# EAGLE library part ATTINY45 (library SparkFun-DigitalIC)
Atmel 8-pin 2/4/8kB flash uC

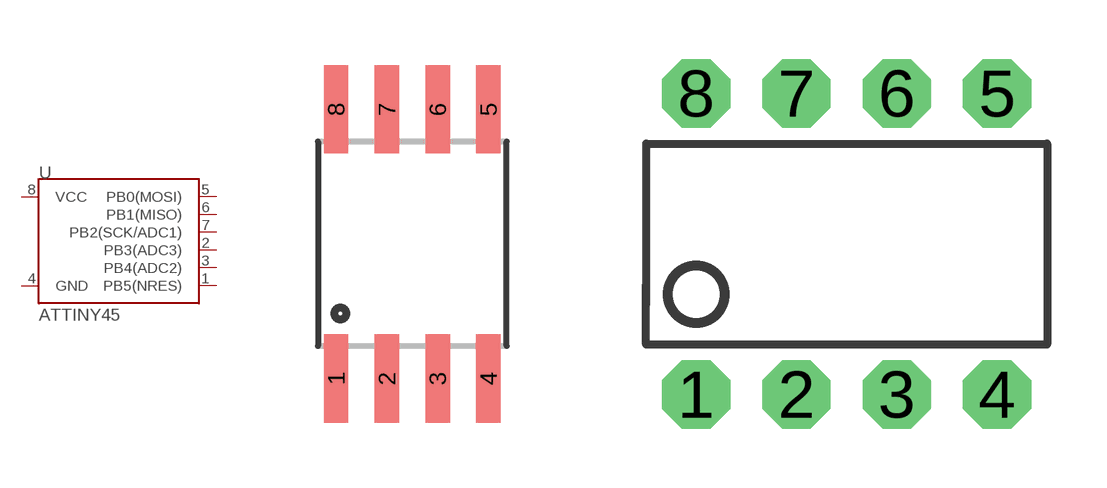
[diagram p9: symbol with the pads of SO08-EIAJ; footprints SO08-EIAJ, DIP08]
Designator prefix U

## ATTINY45TINY45-20-SMT (PROD_ID: IC-08922; VALUE: Tiny45-20-SMT)  [SO08-EIAJ]
1  PB5(NRES)
2  PB3(ADC3)
3  PB4(ADC2)
4  GND
5  PB0(MOSI)
6  PB1(MISO)
7  PB2(SCK/ADC1)
8  VCC

## ATTINY45TINY45-20-DIP (PROD_ID: IC-09439; VALUE: TINY45-20-DIP)  [DIP08]
Pads as for SO08-EIAJ

## ATTINY45TINY85-20-DIP (PROD_ID: IC-09445; VALUE: TINY85-20-DIP)  [DIP08]
Pads as for SO08-EIAJ

## ATTINY45TINY85-20-SMT (PROD_ID: IC-09092; VALUE: Tiny85-20-SMT)  [SO08-EIAJ]
Pads as for SO08-EIAJ

## Footprint SO08-EIAJ (pad centres in mm)
Fits EIAJ packages (wide version of the SOIC-8).
smd 0.61 x 2.21: 1 -1.905,-3.378; 2 -0.635,-3.378; 3 0.635,-3.378; 4 1.905,-3.378; 5 1.905,3.353; 6 0.635,3.353; 7 -0.635,3.353; 8 -1.905,3.353

## Footprint DIP08 (pad centres in mm)
Dual In Line
drill 0.813 pad 1.727 octagon: 1 -3.81,-3.81; 2 -1.27,-3.81; 3 1.27,-3.81; 4 3.81,-3.81; 5 3.81,3.81; 6 1.27,3.81; 7 -1.27,3.81; 8 -3.81,3.81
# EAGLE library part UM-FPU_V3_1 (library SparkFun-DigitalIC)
Micromega floating point coprocessor

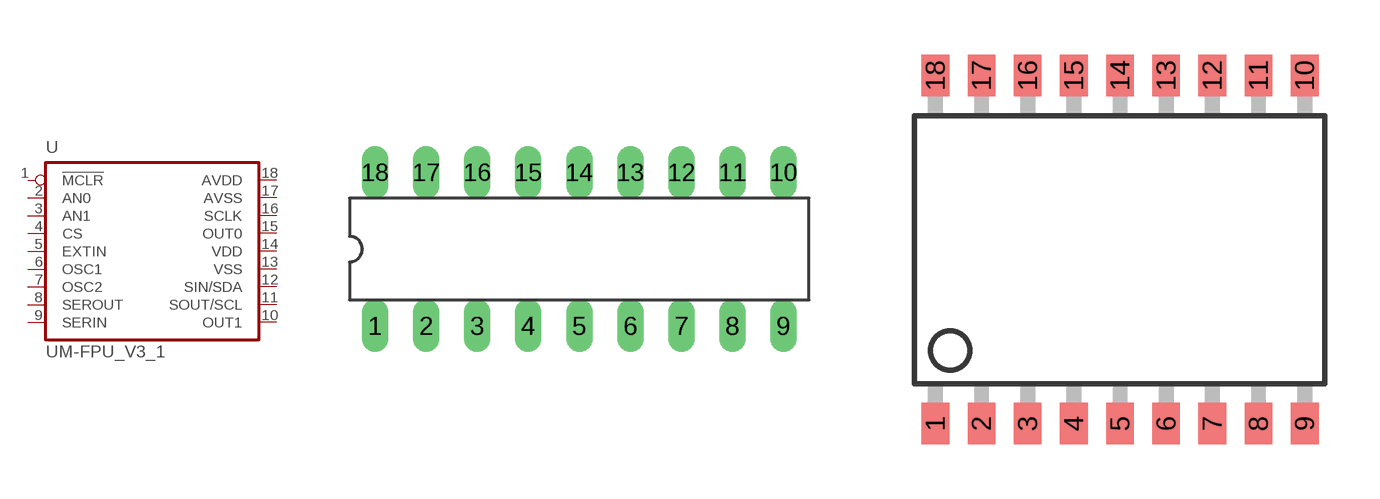
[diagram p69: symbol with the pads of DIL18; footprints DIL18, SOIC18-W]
Designator prefix -

## UM-FPU_V3_1DIL  [DIL18]
1  !MCLR  in
2  AN0  in
3  AN1  in
4  CS  in
5  EXTIN  in
6  OSC1  in
7  OSC2  in
8  SEROUT  out
9  SERIN  in
10  OUT1  out
11  SOUT/SCL  out
12  SIN/SDA  in
13  VSS  pwr
14  VDD  pwr
15  OUT0  out
16  SCLK  in
17  AVSS  pwr
18  AVDD  pwr

## UM-FPU_V3_1SO  [SOIC18-W]
Pads as for DIL18

## Footprint DIL18 (pad centres in mm)
Dual In Line package type P
drill 0.813 long: 1 -10.16,-3.81; 2 -7.62,-3.81; 3 -5.08,-3.81; 4 -2.54,-3.81; 5 0,-3.81; 6 2.54,-3.81; 7 5.08,-3.81; 8 7.62,-3.81; 9 10.16,-3.81; 10 10.16,3.81; 11 7.62,3.81; 12 5.08,3.81; 13 2.54,3.81; 14 0,3.81; 15 -2.54,3.81; 16 -5.08,3.81; 17 -7.62,3.81; 18 -10.16,3.81

## Footprint SOIC18-W (pad centres in mm)
smd 0.762 x 1.143: 1 -5.08,-4.788; 2 -3.81,-4.788; 3 -2.54,-4.788; 4 -1.27,-4.788; 5 0,-4.788; 6 1.27,-4.788; 7 2.54,-4.788; 8 3.81,-4.788; 9 5.08,-4.788; 10 5.08,4.788; 11 3.81,4.788; 12 2.54,4.788; 13 1.27,4.788; 14 0,4.788; 15 -1.27,4.788; 16 -2.54,4.788; 17 -3.81,4.788; 18 -5.08,4.788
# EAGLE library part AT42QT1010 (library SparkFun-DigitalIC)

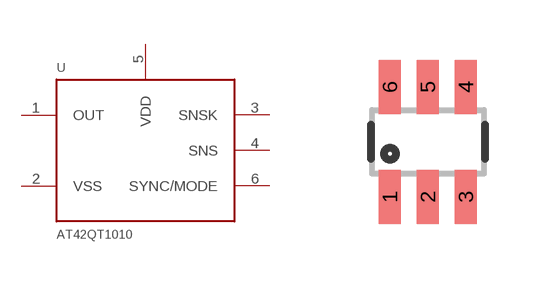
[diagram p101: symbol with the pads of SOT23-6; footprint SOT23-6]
Designator prefix -

## AT42QT1010SOT23  [SOT23-6]
1  OUT
2  VSS
3  SNSK
4  SNS
5  VDD
6  SYNC/MODE

## Footprint SOT23-6 (pad centres in mm)
smd 0.55 x 1.35: 1 -0.95,-1.375; 2 0,-1.375; 3 0.95,-1.375; 4 0.95,1.375; 5 0,1.375; 6 -0.95,1.375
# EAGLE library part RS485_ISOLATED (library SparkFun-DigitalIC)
Isolated RS485 Transceiver. With transformer driver for isloated supply. Fits TI parts such as ISO53T (3.3V only, iMbps), ISO3086T (3.3V or 5V, 20 Mbps). Footprint unproven.

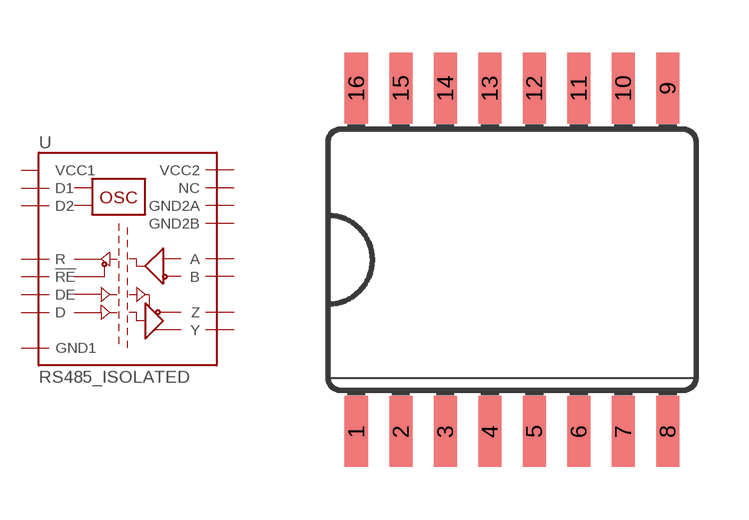
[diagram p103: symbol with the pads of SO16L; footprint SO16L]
Designator prefix U

## RS485_ISOLATED  [SO16L]
1  D1
2  D2
3  GND1
4  VCC1
5  R
6  !RE
7  DE
8  D
9  GND2B
10  NC
11  Y
12  Z
13  B
14  A
15  GND2A
16  VCC2

## Footprint SO16L (pad centres in mm)
Small Outline Package .300 SIOC Source: http://www.maxim-ic.com/cgi-bin/packages?pkg=16%2FSOIC%2E300&Type=Max
smd 0.66 x 2.032: 1 -4.445,-4.902; 2 -3.175,-4.902; 3 -1.905,-4.902; 4 -0.635,-4.902; 5 0.635,-4.902; 6 1.905,-4.902; 7 3.175,-4.902; 8 4.445,-4.902; 9 4.445,4.902; 10 3.175,4.902; 11 1.905,4.902; 12 0.635,4.902; 13 -0.635,4.902; 14 -1.905,4.902; 15 -3.175,4.902; 16 -4.445,4.902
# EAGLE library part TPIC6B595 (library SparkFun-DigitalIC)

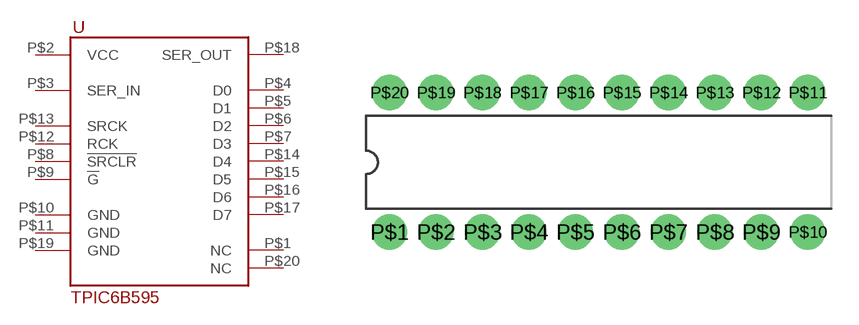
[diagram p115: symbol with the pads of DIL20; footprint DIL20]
Designator prefix -

## TPIC6B595  [DIL20]
P$1  NC  nc
P$2  VCC  pwr
P$3  SER_IN  in
P$4  D0  out
P$5  D1  out
P$6  D2  out
P$7  D3  out
P$8  !SRCLR  in
P$9  !G  in
P$10  GND  pwr
P$11  GND  pwr
P$12  RCK  in
P$13  SRCK  in
P$14  D4  out
P$15  D5  out
P$16  D6  out
P$17  D7  out
P$18  SER_OUT  out
P$19  GND  pwr
P$20  NC  nc

## Footprint DIL20 (pad centres in mm)
drill 1.016 pad 1.93: P$1 1.27,2.54; P$2 3.81,2.54; P$3 6.35,2.54; P$4 8.89,2.54; P$5 11.43,2.54; P$6 13.97,2.54; P$7 16.51,2.54; P$8 19.05,2.54; P$9 21.59,2.54; P$10 24.13,2.54; P$11 24.13,10.16; P$12 21.59,10.16; P$13 19.05,10.16; P$14 16.51,10.16; P$15 13.97,10.16; P$16 11.43,10.16; P$17 8.89,10.16; P$18 6.35,10.16; P$19 3.81,10.16; P$20 1.27,10.16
